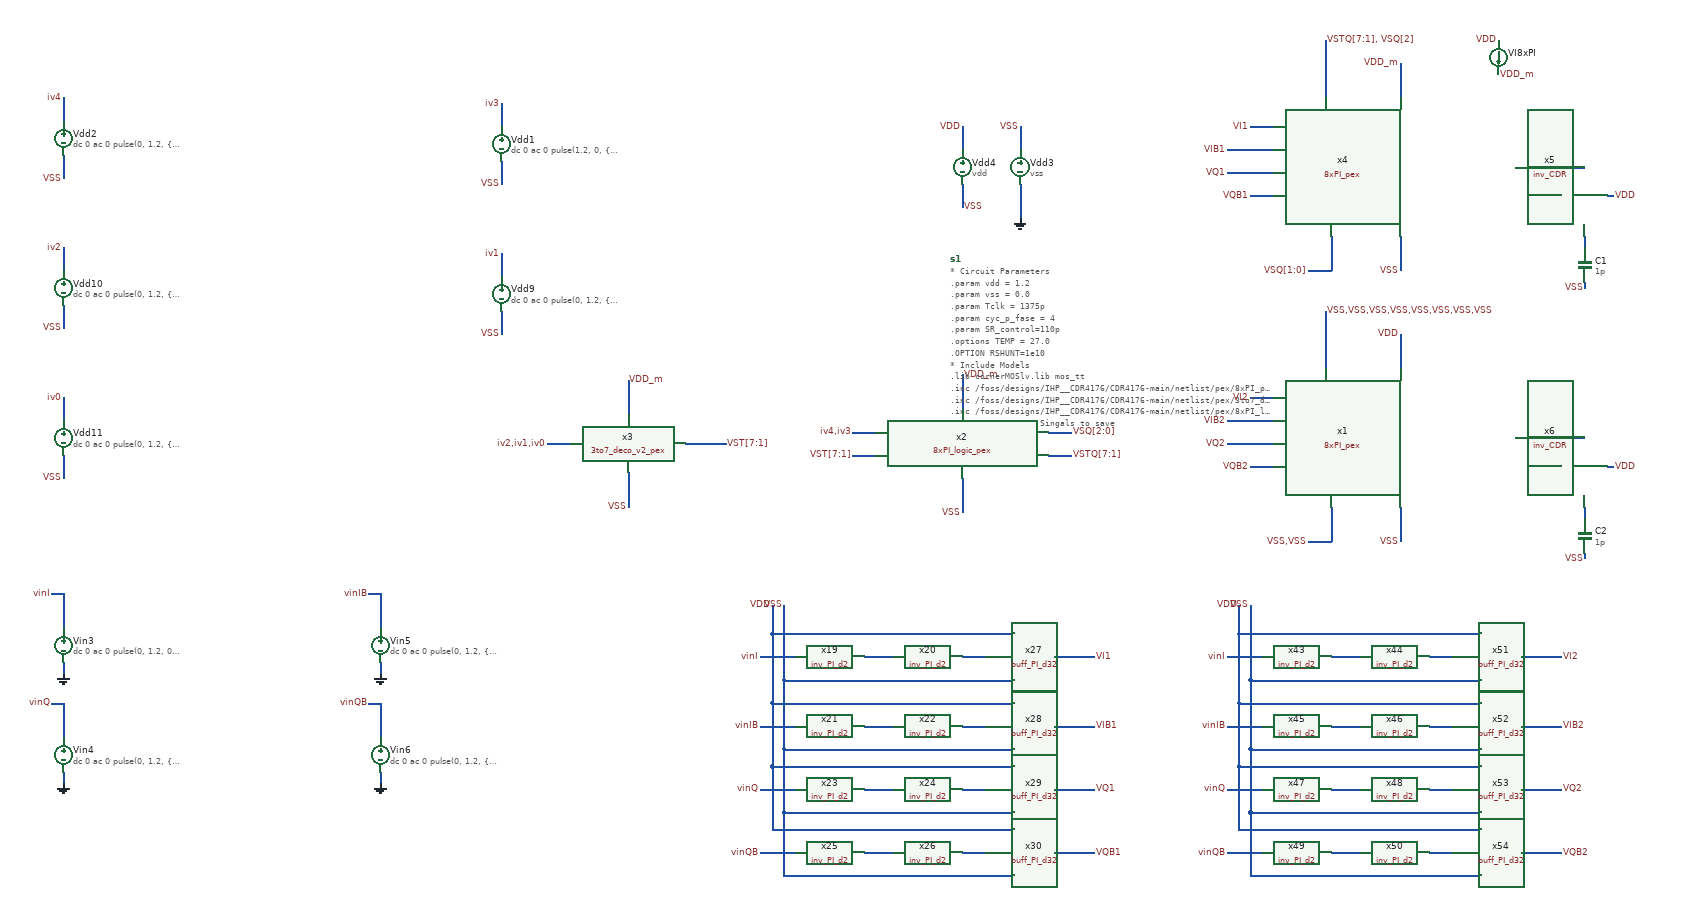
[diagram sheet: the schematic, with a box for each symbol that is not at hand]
v {xschem version=3.4.8RC file_version=1.2}
G {}
K {}
V {}
S {}
F {}
E {}
N -1720 -250 -1720 -210 {lab=iv2}
N -960 -240 -960 -200 {lab=iv1}
N -1720 -150 -1720 -110 {lab=VSS}
N -960 -140 -960 -100 {lab=VSS}
N -1720 10 -1720 50 {lab=iv0}
N -1720 110 -1720 150 {lab=VSS}
N -1720 -510 -1720 -470 {lab=iv4}
N -960 -500 -960 -460 {lab=iv3}
N -960 -400 -960 -360 {lab=VSS}
N -1720 -410 -1720 -370 {lab=VSS}
N 470 -610 470 -510 {lab="VSTQ[7:1], VSQ[2]"}
N -640 90 -570 90 {lab=VST[7:1]}
N 600 -270 600 -210 {lab=VSS}
N 800 -390 860 -390 {lab=vout}
N -160 150 -160 210 {lab=VSS}
N -740 -20 -740 40 {lab=VDD_m}
N -880 90 -840 90 {lab=iv2,iv1,iv0}
N 480 -270 480 -210 {lab=VSQ[1:0]}
N 440 -210 480 -210 {lab=VSQ[1:0]}
N -350 70 -310 70 {lab=iv4,iv3}
N -10 70 30 70 {lab=VSQ[2:0]}
N -350 110 -310 110 {lab=VST[7:1]}
N -10 110 30 110 {lab=VSTQ[7:1]}
N -160 -30 -160 30 {lab=VDD_m}
N -740 140 -740 200 {lab=VSS}
N 340 -460 380 -460 {lab=VI1}
N 300 -420 380 -420 {lab=VIB1}
N 340 -340 380 -340 {lab=VQB1}
N 300 -380 380 -380 {lab=VQ1}
N -160 -460 -160 -420 {lab=VDD}
N -60 -360 -60 -300 {
lab=GND}
N -60 -460 -60 -420 {lab=VSS}
N -160 -360 -160 -320 {lab=VSS}
N -1720 470 -1720 490 {
lab=GND}
N -1720 350 -1720 410 {
lab=vinI}
N -1740 350 -1720 350 {
lab=vinI}
N -1720 660 -1720 680 {
lab=GND}
N -1720 540 -1720 600 {
lab=vinQ}
N -1740 540 -1720 540 {
lab=vinQ}
N -1170 470 -1170 490 {
lab=GND}
N -1170 350 -1170 410 {
lab=vinIB}
N -1190 350 -1170 350 {
lab=vinIB}
N -1170 540 -1170 600 {
lab=vinQB}
N -1190 540 -1170 540 {
lab=vinQB}
N -1170 660 -1170 680 {
lab=GND}
N -160 460 -120 460 {lab=#net1}
N -160 580 -120 580 {lab=#net2}
N -160 690 -120 690 {lab=#net3}
N -160 800 -120 800 {lab=#net4}
N -330 460 -280 460 {lab=#net5}
N -330 580 -280 580 {lab=#net6}
N -330 690 -280 690 {lab=#net7}
N -330 800 -280 800 {lab=#net8}
N -490 650 -490 760 {lab=VDD}
N -470 730 -470 840 {lab=VSS}
N -470 840 -70 840 {lab=VSS}
N -470 730 -70 730 {lab=VSS}
N -470 620 -470 730 {lab=VSS}
N -470 620 -70 620 {lab=VSS}
N -470 500 -470 620 {lab=VSS}
N -470 500 -70 500 {lab=VSS}
N -490 370 -490 420 {lab=VDD}
N -490 540 -70 540 {lab=VDD}
N -490 420 -490 540 {lab=VDD}
N -490 650 -70 650 {lab=VDD}
N -490 540 -490 650 {lab=VDD}
N -490 760 -70 760 {lab=VDD}
N -510 460 -450 460 {lab=vinI}
N -510 580 -450 580 {lab=vinIB}
N -510 690 -450 690 {lab=vinQ}
N -510 800 -450 800 {lab=vinQB}
N -490 420 -70 420 {lab=VDD}
N -470 370 -470 500 {lab=VSS}
N 0 460 70 460 {lab=VI1}
N 0 580 70 580 {lab=VIB1}
N 0 690 70 690 {lab=VQ1}
N 0 800 70 800 {lab=VQB1}
N 470 -140 470 -40 {lab=VSS,VSS,VSS,VSS,VSS,VSS,VSS,VSS}
N 600 200 600 260 {lab=VSS}
N 800 80 860 80 {lab=v8i}
N 480 200 480 260 {lab=VSS,VSS}
N 440 260 480 260 {lab=VSS,VSS}
N 340 10 380 10 {lab=VI2}
N 300 50 380 50 {lab=VIB2}
N 340 130 380 130 {lab=VQB2}
N 300 90 380 90 {lab=VQ2}
N 600 -100 600 -40 {lab=VDD}
N 920 -270 920 -250 {lab=#net9}
N 960 -340 970 -340 {lab=VDD}
N 870 -340 880 -340 {lab=VSS}
N 920 -190 920 -180 {lab=VSS}
N 860 -390 920 -390 {lab=vout}
N 920 200 920 220 {lab=#net10}
N 960 130 970 130 {lab=VDD}
N 870 130 880 130 {lab=VSS}
N 920 280 920 290 {lab=VSS}
N 860 80 920 80 {lab=v8i}
N 860 -430 860 -390 {lab=vout}
N 860 30 860 80 {lab=v8i}
N 600 -570 600 -510 {lab=VDD_m}
N 650 460 690 460 {lab=#net11}
N 650 580 690 580 {lab=#net12}
N 650 690 690 690 {lab=#net13}
N 650 800 690 800 {lab=#net14}
N 480 460 530 460 {lab=#net15}
N 480 580 530 580 {lab=#net16}
N 480 690 530 690 {lab=#net17}
N 480 800 530 800 {lab=#net18}
N 320 650 320 760 {lab=VDD}
N 340 730 340 840 {lab=VSS}
N 340 840 740 840 {lab=VSS}
N 340 730 740 730 {lab=VSS}
N 340 620 340 730 {lab=VSS}
N 340 620 740 620 {lab=VSS}
N 340 500 340 620 {lab=VSS}
N 340 500 740 500 {lab=VSS}
N 320 370 320 420 {lab=VDD}
N 320 540 740 540 {lab=VDD}
N 320 420 320 540 {lab=VDD}
N 320 650 740 650 {lab=VDD}
N 320 540 320 650 {lab=VDD}
N 320 760 740 760 {lab=VDD}
N 300 460 360 460 {lab=vinI}
N 300 580 360 580 {lab=vinIB}
N 300 690 360 690 {lab=vinQ}
N 300 800 360 800 {lab=vinQB}
N 320 420 740 420 {lab=VDD}
N 340 370 340 500 {lab=VSS}
N 810 460 880 460 {lab=VI2}
N 810 580 880 580 {lab=VIB2}
N 810 690 880 690 {lab=VQ2}
N 810 800 880 800 {lab=VQB2}
C {devices/vsource.sym} -960 -170 0 0 {name=Vdd9 value="dc 0 ac 0 pulse(0, 1.2, \{2*cyc_p_fase*Tclk\},\{SR_control\},\{SR_control\}, \{2*cyc_p_fase*Tclk\}, \{4*cyc_p_fase*Tclk\})"}
C {devices/vsource.sym} -1720 -180 0 0 {name=Vdd10 value="dc 0 ac 0 pulse(0, 1.2, \{4*cyc_p_fase*Tclk\},\{SR_control\},\{SR_control\}, \{4*cyc_p_fase*Tclk\}, \{8*cyc_p_fase*Tclk\}) "}
C {devices/lab_pin.sym} -1720 -250 0 0 {name=p49 sig_type=std_logic lab=iv2}
C {devices/lab_pin.sym} -960 -240 0 0 {name=p50 sig_type=std_logic lab=iv1}
C {devices/vsource.sym} -1720 80 0 0 {name=Vdd11 value="dc 0 ac 0 pulse(0, 1.2, \{cyc_p_fase*Tclk\},\{SR_control\},\{SR_control\}, \{cyc_p_fase*Tclk\}, \{2*cyc_p_fase*Tclk\})"}
C {devices/lab_pin.sym} -1720 10 0 0 {name=p53 sig_type=std_logic lab=iv0}
C {devices/vsource.sym} -960 -430 0 0 {name=Vdd1 value="dc 0 ac 0 pulse(1.2, 0, \{8*cyc_p_fase*Tclk\},\{SR_control\},\{SR_control\}, \{8*cyc_p_fase*Tclk\}, \{16*cyc_p_fase*Tclk\})"}
C {devices/vsource.sym} -1720 -440 0 0 {name=Vdd2 value="dc 0 ac 0 pulse(0, 1.2, \{24*cyc_p_fase*Tclk\},\{SR_control\},\{SR_control\}, \{16*cyc_p_fase*Tclk\}, \{40*cyc_p_fase*Tclk\}) "}
C {devices/lab_pin.sym} -1720 -510 0 0 {name=p11 sig_type=std_logic lab=iv4}
C {devices/lab_pin.sym} -960 -500 0 0 {name=p10 sig_type=std_logic lab=iv3}
C {devices/lab_pin.sym} -1720 -370 0 0 {name=p1 sig_type=std_logic lab=VSS}
C {devices/lab_pin.sym} -960 -360 0 0 {name=p2 sig_type=std_logic lab=VSS}
C {devices/lab_pin.sym} -1720 -110 0 0 {name=p3 sig_type=std_logic lab=VSS}
C {devices/lab_pin.sym} -960 -100 0 0 {name=p4 sig_type=std_logic lab=VSS}
C {devices/lab_pin.sym} -1720 150 0 0 {name=p6 sig_type=std_logic lab=VSS}
C {devices/lab_pin.sym} -160 210 0 0 {name=p14 sig_type=std_logic lab=VSS}
C {devices/lab_pin.sym} -740 -20 2 0 {name=p15 sig_type=std_logic lab=VDD_m}
C {devices/lab_pin.sym} -880 90 0 0 {name=p17 sig_type=std_logic lab="iv2,iv1,iv0"}
C {devices/lab_pin.sym} -350 70 0 0 {name=p18 sig_type=std_logic lab="iv4,iv3"}
C {devices/lab_pin.sym} -570 90 2 0 {name=p19 sig_type=std_logic lab=VST[7:1]}
C {devices/lab_pin.sym} 470 -610 2 0 {name=p20 sig_type=std_logic lab="VSTQ[7:1], VSQ[2]"}
C {devices/lab_pin.sym} 30 70 2 0 {name=p21 sig_type=std_logic lab=VSQ[2:0]}
C {devices/lab_pin.sym} 440 -210 0 0 {name=p22 sig_type=std_logic lab=VSQ[1:0]}
C {devices/lab_pin.sym} -350 110 0 0 {name=p23 sig_type=std_logic lab=VST[7:1]}
C {devices/lab_pin.sym} 30 110 2 0 {name=p24 sig_type=std_logic lab=VSTQ[7:1]}
C {devices/lab_pin.sym} -160 -30 2 0 {name=p25 sig_type=std_logic lab=VDD_m}
C {devices/lab_pin.sym} -740 200 0 0 {name=p26 sig_type=std_logic lab=VSS}
C {devices/lab_pin.sym} 300 -420 0 0 {name=p28 sig_type=std_logic lab=VIB1}
C {devices/lab_pin.sym} 340 -340 0 0 {name=p29 sig_type=std_logic lab=VQB1}
C {devices/lab_pin.sym} 300 -380 0 0 {name=p30 sig_type=std_logic lab=VQ1}
C {netlist_not_shown.sym} -180 -230 0 0 {name=s1 only_toplevel=true 

value="

* Circuit Parameters
.param vdd = 1.2
.param vss = 0.0
.param Tclk = 1375p
.param cyc_p_fase = 4
.param SR_control=110p
.options TEMP = 27.0
.OPTION RSHUNT=1e10

* Include Models
.lib cornerMOSlv.lib mos_tt
.inc /foss/designs/IHP__CDR4176/CDR4176-main/netlist/pex/8xPI_pex.spice
.inc /foss/designs/IHP__CDR4176/CDR4176-main/netlist/pex/3to7_deco_v2_pex.spice
.inc /foss/designs/IHP__CDR4176/CDR4176-main/netlist/pex/8xPI_logic_pex.spice

* OP Parameters & Singals to save
*.save V(vout) V(v8i) I(VI8xPI)
.save V(vout) V(v8i) V(vinI) V(vinIB) V(vinQ) V(vinQB) V(vsq[2]) V(vsq[1]) V(vsq[0]) V(vst[7]) V(vst[6]) V(vst[5]) V(vst[4]) V(vst[3]) V(vst[2]) V(vst[1]) V(vstq[7]) V(vstq[6]) V(vstq[5]) V(vstq[4]) V(vstq[3]) V(vstq[2]) V(vstq[1]) V(vi1) V(vib1) V(vq1) V(vqb1) V(iv4) V(iv3) V(iv2) V(iv1) V(iv0)

*Simulations
.control
	set output_path = ../../verification/python/
	set ngdebug
	set verbose
	tran 5PS 221NS
	set filetype = ascii
        write \{$output_path\}tran_linearity_8xPI_pex.raw 
.endc
.end"}
C {devices/vsource.sym} -160 -390 0 0 {name=Vdd4 value=vdd}
C {devices/lab_pin.sym} -160 -460 0 0 {name=p5 sig_type=std_logic lab=VDD}
C {devices/vsource.sym} -60 -390 0 0 {name=Vdd3 value=vss}
C {devices/gnd.sym} -60 -300 0 0 {name=l6 lab=GND}
C {devices/lab_pin.sym} -60 -460 0 0 {name=p9 sig_type=std_logic lab=VSS}
C {devices/lab_pin.sym} -160 -320 2 0 {name=p13 sig_type=std_logic lab=VSS}
C {devices/gnd.sym} -1720 490 0 0 {name=l2 lab=GND}
C {devices/vsource.sym} -1720 440 0 0 {name=Vin3 value="dc 0 ac 0 pulse(0, 1.2, 0, \{SR_control/2\}, \{SR_control/2\}, \{Tclk/2-SR_control/2\}, Tclk) "}
C {devices/lab_pin.sym} -1740 350 0 0 {name=p16 sig_type=std_logic lab=vinI}
C {devices/lab_pin.sym} -1740 540 0 0 {name=p31 sig_type=std_logic lab=vinQ}
C {devices/vsource.sym} -1720 630 0 0 {name=Vin4 value="dc 0 ac 0 pulse(0, 1.2, \{Tclk/4\}, \{SR_control/2\}, \{SR_control/2\}, \{Tclk/2-SR_control/2\}, Tclk) "}
C {devices/gnd.sym} -1170 490 0 0 {name=l4 lab=GND}
C {devices/vsource.sym} -1170 440 0 0 {name=Vin5 value="dc 0 ac 0 pulse(0, 1.2, \{Tclk/2\}, \{SR_control/2\}, \{SR_control/2\}, \{Tclk/2-SR_control/2\}, Tclk) "}
C {devices/lab_pin.sym} -1190 350 0 0 {name=p32 sig_type=std_logic lab=vinIB}
C {devices/vsource.sym} -1170 630 0 0 {name=Vin6 value="dc 0 ac 0 pulse(0, 1.2, \{3*Tclk/4\}, \{SR_control/2\}, \{SR_control/2\}, \{Tclk/2-SR_control/2\}, Tclk) "}
C {devices/lab_pin.sym} -1190 540 0 0 {name=p33 sig_type=std_logic lab=vinQB}
C {devices/gnd.sym} -1720 680 0 0 {name=l3 lab=GND}
C {devices/gnd.sym} -1170 680 0 0 {name=l5 lab=GND}
C {devices/lab_pin.sym} 70 460 0 1 {name=p35 sig_type=std_logic lab=VI1}
C {devices/lab_pin.sym} 340 -460 0 0 {name=p38 sig_type=std_logic lab=VI1}
C {devices/lab_pin.sym} 70 690 0 1 {name=p39 sig_type=std_logic lab=VQ1}
C {devices/lab_pin.sym} 70 800 0 1 {name=p40 sig_type=std_logic lab=VQB1}
C {devices/lab_pin.sym} 70 580 0 1 {name=p37 sig_type=std_logic lab=VIB1}
C {devices/lab_pin.sym} 600 -570 0 0 {name=p7 sig_type=std_logic lab=VDD_m}
C {devices/lab_pin.sym} 600 -210 0 0 {name=p8 sig_type=std_logic lab=VSS}
C {ammeter.sym} 770 -580 0 0 {name=VI8xPI savecurrent=true spice_ignore=0}
C {devices/lab_pin.sym} 470 -140 2 0 {name=p47 sig_type=std_logic lab="VSS,VSS,VSS,VSS,VSS,VSS,VSS,VSS"}
C {devices/lab_pin.sym} 440 260 0 0 {name=p48 sig_type=std_logic lab="VSS,VSS"}
C {devices/lab_pin.sym} 300 50 0 0 {name=p52 sig_type=std_logic lab=VIB2}
C {devices/lab_pin.sym} 340 130 0 0 {name=p54 sig_type=std_logic lab=VQB2}
C {devices/lab_pin.sym} 300 90 0 0 {name=p55 sig_type=std_logic lab=VQ2}
C {devices/lab_pin.sym} 340 10 0 0 {name=p58 sig_type=std_logic lab=VI2}
C {devices/lab_pin.sym} 600 -100 0 0 {name=p59 sig_type=std_logic lab=VDD}
C {devices/lab_pin.sym} 600 260 0 0 {name=p60 sig_type=std_logic lab=VSS}
C {capa.sym} 920 -220 0 0 {name=C1
m=1
value=1p
footprint=1206
device="ceramic capacitor"
}
C {devices/lab_pin.sym} 970 -340 2 0 {name=p68 sig_type=std_logic lab=VDD}
C {devices/lab_pin.sym} 870 -340 0 0 {name=p69 sig_type=std_logic lab=VSS}
C {devices/lab_pin.sym} 920 -180 3 0 {name=p70 sig_type=std_logic lab=VSS}
C {capa.sym} 920 250 0 0 {name=C2
m=1
value=1p
footprint=1206
device="ceramic capacitor"
}
C {devices/lab_pin.sym} 970 130 2 0 {name=p12 sig_type=std_logic lab=VDD}
C {devices/lab_pin.sym} 870 130 0 0 {name=p61 sig_type=std_logic lab=VSS}
C {devices/lab_pin.sym} 920 290 3 0 {name=p62 sig_type=std_logic lab=VSS}
C {devices/lab_pin.sym} 860 -430 1 0 {name=p63 sig_type=std_logic lab=vout}
C {devices/lab_pin.sym} 860 30 1 0 {name=p64 sig_type=std_logic lab=v8i}
C {devices/lab_pin.sym} 770 -610 0 0 {name=p27 sig_type=std_logic lab=VDD}
C {devices/lab_pin.sym} 770 -550 2 0 {name=p34 sig_type=std_logic lab=VDD_m}
C {devices/lab_pin.sym} -490 370 1 0 {name=p65 sig_type=std_logic lab=VDD}
C {devices/lab_pin.sym} -470 370 1 0 {name=p66 sig_type=std_logic lab=VSS}
C {devices/lab_pin.sym} -510 460 0 0 {name=p67 sig_type=std_logic lab=vinI}
C {devices/lab_pin.sym} -510 580 0 0 {name=p71 sig_type=std_logic lab=vinIB}
C {devices/lab_pin.sym} -510 690 0 0 {name=p72 sig_type=std_logic lab=vinQ}
C {devices/lab_pin.sym} -510 800 0 0 {name=p73 sig_type=std_logic lab=vinQB}
C {inv_PI_d2/inv_PI_d2.sym} -400 460 0 0 {name=x19}
C {inv_PI_d2/inv_PI_d2.sym} -230 460 0 0 {name=x20}
C {inv_PI_d2/inv_PI_d2.sym} -400 580 0 0 {name=x21}
C {inv_PI_d2/inv_PI_d2.sym} -230 580 0 0 {name=x22}
C {inv_PI_d2/inv_PI_d2.sym} -400 690 0 0 {name=x23}
C {inv_PI_d2/inv_PI_d2.sym} -230 690 0 0 {name=x24}
C {inv_PI_d2/inv_PI_d2.sym} -400 800 0 0 {name=x25}
C {inv_PI_d2/inv_PI_d2.sym} -230 800 0 0 {name=x26}
C {buff_PI_d32/buff_PI_d32.sym} -70 460 0 0 {name=x27}
C {buff_PI_d32/buff_PI_d32.sym} -70 580 0 0 {name=x28}
C {buff_PI_d32/buff_PI_d32.sym} -70 690 0 0 {name=x29}
C {buff_PI_d32/buff_PI_d32.sym} -70 800 0 0 {name=x30}
C {devices/lab_pin.sym} 880 460 0 1 {name=p74 sig_type=std_logic lab=VI2}
C {devices/lab_pin.sym} 880 690 0 1 {name=p75 sig_type=std_logic lab=VQ2}
C {devices/lab_pin.sym} 880 800 0 1 {name=p76 sig_type=std_logic lab=VQB2}
C {devices/lab_pin.sym} 880 580 0 1 {name=p77 sig_type=std_logic lab=VIB2}
C {devices/lab_pin.sym} 320 370 1 0 {name=p88 sig_type=std_logic lab=VDD}
C {devices/lab_pin.sym} 340 370 1 0 {name=p89 sig_type=std_logic lab=VSS}
C {devices/lab_pin.sym} 300 460 0 0 {name=p90 sig_type=std_logic lab=vinI}
C {devices/lab_pin.sym} 300 580 0 0 {name=p91 sig_type=std_logic lab=vinIB}
C {devices/lab_pin.sym} 300 690 0 0 {name=p92 sig_type=std_logic lab=vinQ}
C {devices/lab_pin.sym} 300 800 0 0 {name=p93 sig_type=std_logic lab=vinQB}
C {inv_PI_d2/inv_PI_d2.sym} 410 460 0 0 {name=x43}
C {inv_PI_d2/inv_PI_d2.sym} 580 460 0 0 {name=x44}
C {inv_PI_d2/inv_PI_d2.sym} 410 580 0 0 {name=x45}
C {inv_PI_d2/inv_PI_d2.sym} 580 580 0 0 {name=x46}
C {inv_PI_d2/inv_PI_d2.sym} 410 690 0 0 {name=x47}
C {inv_PI_d2/inv_PI_d2.sym} 580 690 0 0 {name=x48}
C {inv_PI_d2/inv_PI_d2.sym} 410 800 0 0 {name=x49}
C {inv_PI_d2/inv_PI_d2.sym} 580 800 0 0 {name=x50}
C {buff_PI_d32/buff_PI_d32.sym} 740 460 0 0 {name=x51}
C {buff_PI_d32/buff_PI_d32.sym} 740 580 0 0 {name=x52}
C {buff_PI_d32/buff_PI_d32.sym} 740 690 0 0 {name=x53}
C {buff_PI_d32/buff_PI_d32.sym} 740 800 0 0 {name=x54}
C {3to7_deco_v2/3to7_deco_v2_pex.sym} -870 160 0 0 {name=x3}
C {8xPI_logic/8xPI_logic_pex.sym} -160 90 0 0 {name=x2}
C {8xPI/8xPI_pex.sym} 650 -310 0 0 {name=x4}
C {8xPI/8xPI_pex.sym} 650 160 0 0 {name=x1}
C {inv_CDR/inv_CDR.sym} 780 -430 1 0 {name=x5}
C {inv_CDR/inv_CDR.sym} 780 40 1 0 {name=x6}
